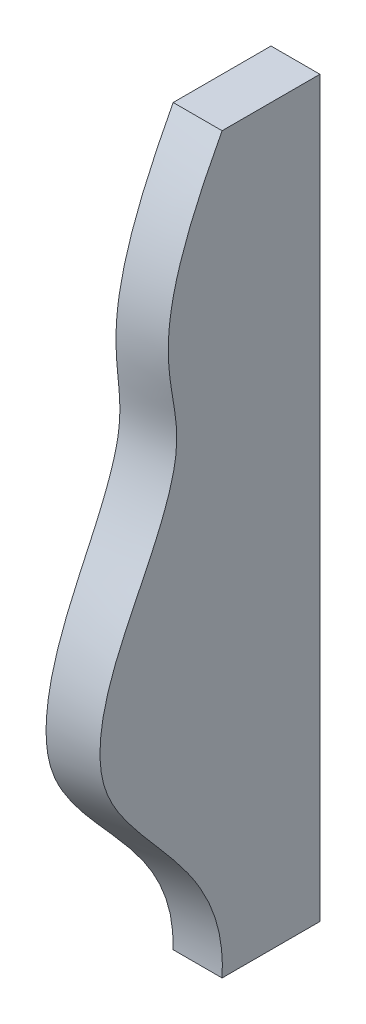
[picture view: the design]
ISO-10303-21;
HEADER;
FILE_DESCRIPTION(('STEP AP214'),'2;1');
FILE_NAME('part.step','',(''),(''),'','','');
FILE_SCHEMA(('AUTOMOTIVE_DESIGN { 1 0 10303 214 1 1 1 1 }'));
ENDSEC;
DATA;
#1=APPLICATION_CONTEXT('core data for automotive mechanical design processes');
#2=APPLICATION_PROTOCOL_DEFINITION('international standard','automotive_design',2000,#1);
#3=PRODUCT_CONTEXT('',#1,'mechanical');
#4=PRODUCT('Part','Part','',(#3));
#5=PRODUCT_RELATED_PRODUCT_CATEGORY('part','',(#4));
#6=PRODUCT_DEFINITION_FORMATION('','',#4);
#7=PRODUCT_DEFINITION_CONTEXT('part definition',#1,'design');
#8=PRODUCT_DEFINITION('design','',#6,#7);
#9=PRODUCT_DEFINITION_SHAPE('','',#8);
#10=(LENGTH_UNIT() NAMED_UNIT(*) SI_UNIT(.MILLI.,.METRE.));
#11=(NAMED_UNIT(*) PLANE_ANGLE_UNIT() SI_UNIT($,.RADIAN.));
#12=(NAMED_UNIT(*) SI_UNIT($,.STERADIAN.) SOLID_ANGLE_UNIT());
#13=UNCERTAINTY_MEASURE_WITH_UNIT(LENGTH_MEASURE(1.E-05),#10,'distance_accuracy_value','');
#14=(GEOMETRIC_REPRESENTATION_CONTEXT(3) GLOBAL_UNCERTAINTY_ASSIGNED_CONTEXT((#13)) GLOBAL_UNIT_ASSIGNED_CONTEXT((#10,
#11,#12)) REPRESENTATION_CONTEXT('',''));
#15=CARTESIAN_POINT('',(0.,0.,0.));
#16=DIRECTION('',(0.,0.,1.));
#17=DIRECTION('',(1.,0.,0.));
#18=AXIS2_PLACEMENT_3D('',#15,#16,#17);
#19=CARTESIAN_POINT('',(150.,375.,253.120113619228));
#20=DIRECTION('',(1.,0.,0.));
#21=DIRECTION('',(0.,0.,-1.));
#22=AXIS2_PLACEMENT_3D('',#19,#20,#21);
#23=PLANE('',#22);
#24=CARTESIAN_POINT('',(150.,375.,100.));
#25=CARTESIAN_POINT('',(150.,373.247296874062,100.949272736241));
#26=CARTESIAN_POINT('',(150.,371.49166332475,101.893144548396));
#27=CARTESIAN_POINT('',(150.,367.973911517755,103.76967532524));
#28=CARTESIAN_POINT('',(150.,366.211791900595,104.702331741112));
#29=CARTESIAN_POINT('',(150.,362.68094876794,106.555742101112));
#30=CARTESIAN_POINT('',(150.,360.912224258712,107.476494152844));
#31=CARTESIAN_POINT('',(150.,357.368027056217,109.305350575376));
#32=CARTESIAN_POINT('',(150.,355.592553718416,110.213453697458));
#33=CARTESIAN_POINT('',(150.,352.03469085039,112.016223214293));
#34=CARTESIAN_POINT('',(150.,350.252300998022,112.910888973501));
#35=CARTESIAN_POINT('',(150.,346.680410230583,114.685941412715));
#36=CARTESIAN_POINT('',(150.,344.89090927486,115.566328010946));
#37=CARTESIAN_POINT('',(150.,341.238005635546,117.344322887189));
#38=CARTESIAN_POINT('',(150.,339.374324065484,118.241358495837));
#39=CARTESIAN_POINT('',(150.,335.638765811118,120.018035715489));
#40=CARTESIAN_POINT('',(150.,333.766889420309,120.897677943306));
#41=CARTESIAN_POINT('',(150.,330.014609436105,122.638410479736));
#42=CARTESIAN_POINT('',(150.,328.134206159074,123.499501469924));
#43=CARTESIAN_POINT('',(150.,324.364498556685,125.20187965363));
#44=CARTESIAN_POINT('',(150.,322.475194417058,126.043167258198));
#45=CARTESIAN_POINT('',(150.,318.687262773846,127.704583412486));
#46=CARTESIAN_POINT('',(150.,316.788635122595,128.524711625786));
#47=CARTESIAN_POINT('',(150.,312.981585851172,130.142334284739));
#48=CARTESIAN_POINT('',(150.,311.073163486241,130.939826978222));
#49=CARTESIAN_POINT('',(150.,306.842771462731,132.67607155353));
#50=CARTESIAN_POINT('',(150.,304.518466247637,133.609144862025));
#51=CARTESIAN_POINT('',(150.,299.854413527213,135.436354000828));
#52=CARTESIAN_POINT('',(150.,297.51466504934,136.330487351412));
#53=CARTESIAN_POINT('',(150.,292.819220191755,138.076111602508));
#54=CARTESIAN_POINT('',(150.,290.463523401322,138.927601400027));
#55=CARTESIAN_POINT('',(150.,285.735557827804,140.583880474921));
#56=CARTESIAN_POINT('',(150.,283.363287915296,141.388666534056));
#57=CARTESIAN_POINT('',(150.,278.601413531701,142.947089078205));
#58=CARTESIAN_POINT('',(150.,276.211805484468,143.700714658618));
#59=CARTESIAN_POINT('',(150.,271.414338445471,145.151939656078));
#60=CARTESIAN_POINT('',(150.,269.006471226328,145.849511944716));
#61=CARTESIAN_POINT('',(150.,264.23211258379,147.166545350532));
#62=CARTESIAN_POINT('',(150.,261.866031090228,147.787488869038));
#63=CARTESIAN_POINT('',(150.,257.117326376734,148.964920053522));
#64=CARTESIAN_POINT('',(150.,254.73469992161,149.521394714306));
#65=CARTESIAN_POINT('',(150.,249.954521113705,150.563713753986));
#66=CARTESIAN_POINT('',(150.,247.556972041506,151.049573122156));
#67=CARTESIAN_POINT('',(150.,242.748569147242,151.944497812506));
#68=CARTESIAN_POINT('',(150.,240.337721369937,152.353595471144));
#69=CARTESIAN_POINT('',(150.,235.504389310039,153.089037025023));
#70=CARTESIAN_POINT('',(150.,233.081910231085,153.415414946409));
#71=CARTESIAN_POINT('',(150.,228.22708593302,153.979952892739));
#72=CARTESIAN_POINT('',(150.,225.794742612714,154.218129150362));
#73=CARTESIAN_POINT('',(150.,221.202606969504,154.57964961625));
#74=CARTESIAN_POINT('',(150.,219.043610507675,154.713043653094));
#75=CARTESIAN_POINT('',(150.,215.802375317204,154.857056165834));
#76=CARTESIAN_POINT('',(150.,214.721323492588,154.895715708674));
#77=CARTESIAN_POINT('',(150.,212.558715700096,154.954212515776));
#78=CARTESIAN_POINT('',(150.,211.477159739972,154.974050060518));
#79=CARTESIAN_POINT('',(150.,209.313700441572,154.994876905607));
#80=CARTESIAN_POINT('',(150.,208.231797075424,154.995863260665));
#81=CARTESIAN_POINT('',(150.,206.06815198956,154.979082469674));
#82=CARTESIAN_POINT('',(150.,204.986410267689,154.961315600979));
#83=CARTESIAN_POINT('',(150.,202.82338573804,154.907267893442));
#84=CARTESIAN_POINT('',(150.,201.742102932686,154.870986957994));
#85=CARTESIAN_POINT('',(150.,199.580299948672,154.780304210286));
#86=CARTESIAN_POINT('',(150.,198.499779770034,154.725902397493));
#87=CARTESIAN_POINT('',(150.,196.340060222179,154.599554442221));
#88=CARTESIAN_POINT('',(150.,195.26086057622,154.52761301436));
#89=CARTESIAN_POINT('',(150.,193.103718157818,154.366915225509));
#90=CARTESIAN_POINT('',(150.,192.025775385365,154.278158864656));
#91=CARTESIAN_POINT('',(150.,189.872196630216,154.08483354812));
#92=CARTESIAN_POINT('',(150.,188.796559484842,153.980277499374));
#93=CARTESIAN_POINT('',(150.,186.646826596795,153.756414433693));
#94=CARTESIAN_POINT('',(150.,185.572730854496,153.637107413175));
#95=CARTESIAN_POINT('',(150.,183.411630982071,153.383350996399));
#96=CARTESIAN_POINT('',(150.,182.324648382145,153.248718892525));
#97=CARTESIAN_POINT('',(150.,180.152274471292,152.967218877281));
#98=CARTESIAN_POINT('',(150.,179.066883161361,152.820350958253));
#99=CARTESIAN_POINT('',(150.,176.897957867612,152.51620875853));
#100=CARTESIAN_POINT('',(150.,175.814423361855,152.358938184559));
#101=CARTESIAN_POINT('',(150.,173.648624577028,152.03591591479));
#102=CARTESIAN_POINT('',(150.,172.566360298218,151.870164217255));
#103=CARTESIAN_POINT('',(150.,170.402658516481,151.532314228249));
#104=CARTESIAN_POINT('',(150.,169.321221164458,151.360214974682));
#105=CARTESIAN_POINT('',(150.,167.158990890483,151.012030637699));
#106=CARTESIAN_POINT('',(150.,166.078197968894,150.835945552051));
#107=CARTESIAN_POINT('',(150.,163.916447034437,150.482217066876));
#108=CARTESIAN_POINT('',(150.,162.835489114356,150.304573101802));
#109=CARTESIAN_POINT('',(150.,160.673385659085,149.950433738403));
#110=CARTESIAN_POINT('',(150.,159.592240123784,149.77393834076));
#111=CARTESIAN_POINT('',(150.,156.346709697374,149.250094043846));
#112=CARTESIAN_POINT('',(150.,154.181366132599,148.908578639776));
#113=CARTESIAN_POINT('',(150.,149.842848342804,148.263753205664));
#114=CARTESIAN_POINT('',(150.,147.669668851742,147.960477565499));
#115=CARTESIAN_POINT('',(150.,143.945168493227,147.494438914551));
#116=CARTESIAN_POINT('',(150.,142.395781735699,147.316405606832));
#117=CARTESIAN_POINT('',(150.,139.292748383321,146.999390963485));
#118=CARTESIAN_POINT('',(150.,137.739101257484,146.860414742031));
#119=CARTESIAN_POINT('',(150.,134.629263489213,146.628850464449));
#120=CARTESIAN_POINT('',(150.,133.073075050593,146.536233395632));
#121=CARTESIAN_POINT('',(150.,129.959950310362,146.40352294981));
#122=CARTESIAN_POINT('',(150.,128.403016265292,146.36337778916));
#123=CARTESIAN_POINT('',(150.,125.290187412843,146.340373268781));
#124=CARTESIAN_POINT('',(150.,123.734293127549,146.357456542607));
#125=CARTESIAN_POINT('',(150.,121.402495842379,146.428465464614));
#126=CARTESIAN_POINT('',(150.,120.625848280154,146.459679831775));
#127=CARTESIAN_POINT('',(150.,119.073310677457,146.537483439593));
#128=CARTESIAN_POINT('',(150.,118.297420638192,146.584072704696));
#129=CARTESIAN_POINT('',(150.,116.754063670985,146.692307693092));
#130=CARTESIAN_POINT('',(150.,115.986586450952,146.753806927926));
#131=CARTESIAN_POINT('',(150.,114.453020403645,146.892166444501));
#132=CARTESIAN_POINT('',(150.,113.686931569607,146.969026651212));
#133=CARTESIAN_POINT('',(150.,112.155915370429,147.138207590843));
#134=CARTESIAN_POINT('',(150.,111.390989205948,147.23053919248));
#135=CARTESIAN_POINT('',(150.,109.863132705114,147.430438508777));
#136=CARTESIAN_POINT('',(150.,109.100202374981,147.538006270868));
#137=CARTESIAN_POINT('',(150.,107.575692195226,147.76738947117));
#138=CARTESIAN_POINT('',(150.,106.814114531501,147.889219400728));
#139=CARTESIAN_POINT('',(150.,105.293205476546,148.146122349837));
#140=CARTESIAN_POINT('',(150.,104.53387408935,148.281195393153));
#141=CARTESIAN_POINT('',(150.,102.257812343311,148.705255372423));
#142=CARTESIAN_POINT('',(150.,100.744522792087,149.012852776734));
#143=CARTESIAN_POINT('',(150.,97.7266105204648,149.671799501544));
#144=CARTESIAN_POINT('',(150.,96.2219937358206,150.023175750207));
#145=CARTESIAN_POINT('',(150.,93.2224352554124,150.764478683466));
#146=CARTESIAN_POINT('',(150.,91.7274928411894,151.15440246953));
#147=CARTESIAN_POINT('',(150.,88.8734457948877,151.934017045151));
#148=CARTESIAN_POINT('',(150.,87.5135768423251,152.320921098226));
#149=CARTESIAN_POINT('',(150.,84.8014690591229,153.120657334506));
#150=CARTESIAN_POINT('',(150.,83.4492304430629,153.533490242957));
#151=CARTESIAN_POINT('',(150.,79.4057115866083,154.80651312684));
#152=CARTESIAN_POINT('',(150.,76.7254442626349,155.701832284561));
#153=CARTESIAN_POINT('',(150.,71.3931373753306,157.572090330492));
#154=CARTESIAN_POINT('',(150.,68.7410970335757,158.547027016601));
#155=CARTESIAN_POINT('',(150.,63.4621878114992,160.564404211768));
#156=CARTESIAN_POINT('',(150.,60.8353249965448,161.606860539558));
#157=CARTESIAN_POINT('',(150.,55.6042279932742,163.748143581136));
#158=CARTESIAN_POINT('',(150.,52.9999978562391,164.846980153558));
#159=CARTESIAN_POINT('',(150.,47.8118804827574,167.090640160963));
#160=CARTESIAN_POINT('',(150.,45.2279907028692,168.235457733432));
#161=CARTESIAN_POINT('',(150.,40.026064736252,170.584884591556));
#162=CARTESIAN_POINT('',(150.,37.4083611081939,171.790228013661));
#163=CARTESIAN_POINT('',(150.,32.1876338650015,174.229472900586));
#164=CARTESIAN_POINT('',(150.,29.5846047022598,175.463362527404));
#165=CARTESIAN_POINT('',(150.,24.3888098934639,177.951046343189));
#166=CARTESIAN_POINT('',(150.,21.796042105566,179.20483607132));
#167=CARTESIAN_POINT('',(150.,16.6164102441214,181.723778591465));
#168=CARTESIAN_POINT('',(150.,14.0295455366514,182.988930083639));
#169=CARTESIAN_POINT('',(150.,8.85734206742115,185.522017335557));
#170=CARTESIAN_POINT('',(150.,6.27200323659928,186.789952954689));
#171=CARTESIAN_POINT('',(150.,1.09839768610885,189.319873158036));
#172=CARTESIAN_POINT('',(150.,-1.48986904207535,190.581857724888));
#173=CARTESIAN_POINT('',(150.,-6.67249249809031,193.090210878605));
#174=CARTESIAN_POINT('',(150.,-9.26684582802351,194.336586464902));
#175=CARTESIAN_POINT('',(150.,-14.4672144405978,196.804881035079));
#176=CARTESIAN_POINT('',(150.,-17.0732297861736,198.026799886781));
#177=CARTESIAN_POINT('',(150.,-22.3012873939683,200.436339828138));
#178=CARTESIAN_POINT('',(150.,-24.9233304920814,201.623959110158));
#179=CARTESIAN_POINT('',(150.,-30.1879778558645,203.95467835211));
#180=CARTESIAN_POINT('',(150.,-32.8305870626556,205.097767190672));
#181=CARTESIAN_POINT('',(150.,-38.141081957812,207.32879450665));
#182=CARTESIAN_POINT('',(150.,-40.8089828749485,208.416696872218));
#183=CARTESIAN_POINT('',(150.,-46.1749850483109,210.52626355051));
#184=CARTESIAN_POINT('',(150.,-48.8731212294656,211.547839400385));
#185=CARTESIAN_POINT('',(150.,-54.2622198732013,213.497694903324));
#186=CARTESIAN_POINT('',(150.,-56.9527951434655,214.427040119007));
#187=CARTESIAN_POINT('',(150.,-62.3651819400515,216.195670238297));
#188=CARTESIAN_POINT('',(150.,-65.0870099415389,217.034904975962));
#189=CARTESIAN_POINT('',(150.,-70.558973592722,218.60899420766));
#190=CARTESIAN_POINT('',(150.,-73.3090901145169,219.343914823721));
#191=CARTESIAN_POINT('',(150.,-78.8346826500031,220.695173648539));
#192=CARTESIAN_POINT('',(150.,-81.6101206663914,221.31166614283));
#193=CARTESIAN_POINT('',(150.,-87.1833836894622,222.411785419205));
#194=CARTESIAN_POINT('',(150.,-89.981172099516,222.895596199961));
#195=CARTESIAN_POINT('',(150.,-95.5964427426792,223.715672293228));
#196=CARTESIAN_POINT('',(150.,-98.4139080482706,224.052051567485));
#197=CARTESIAN_POINT('',(150.,-103.392704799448,224.500985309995));
#198=CARTESIAN_POINT('',(150.,-105.55097045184,224.647721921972));
#199=CARTESIAN_POINT('',(150.,-109.872459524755,224.8387691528));
#200=CARTESIAN_POINT('',(150.,-112.035683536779,224.883066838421));
#201=CARTESIAN_POINT('',(150.,-116.362228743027,224.861610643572));
#202=CARTESIAN_POINT('',(150.,-118.525549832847,224.795829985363));
#203=CARTESIAN_POINT('',(150.,-122.836806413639,224.54717432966));
#204=CARTESIAN_POINT('',(150.,-124.984768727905,224.364774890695));
#205=CARTESIAN_POINT('',(150.,-129.266440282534,223.876347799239));
#206=CARTESIAN_POINT('',(150.,-131.400151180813,223.570334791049));
#207=CARTESIAN_POINT('',(150.,-135.644256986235,222.828518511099));
#208=CARTESIAN_POINT('',(150.,-137.754661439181,222.392770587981));
#209=CARTESIAN_POINT('',(150.,-141.112337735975,221.586138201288));
#210=CARTESIAN_POINT('',(150.,-142.370030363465,221.258050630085));
#211=CARTESIAN_POINT('',(150.,-144.871608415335,220.551969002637));
#212=CARTESIAN_POINT('',(150.,-146.115492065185,220.173968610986));
#213=CARTESIAN_POINT('',(150.,-147.968971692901,219.56920991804));
#214=CARTESIAN_POINT('',(150.,-148.584785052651,219.361314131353));
#215=CARTESIAN_POINT('',(150.,-149.812005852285,218.932879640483));
#216=CARTESIAN_POINT('',(150.,-150.423413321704,218.712341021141));
#217=CARTESIAN_POINT('',(150.,-151.641610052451,218.258652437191));
#218=CARTESIAN_POINT('',(150.,-152.24839875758,218.0255009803));
#219=CARTESIAN_POINT('',(150.,-153.457265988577,217.547307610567));
#220=CARTESIAN_POINT('',(150.,-154.05934448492,217.302265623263));
#221=CARTESIAN_POINT('',(150.,-155.858371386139,216.550323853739));
#222=CARTESIAN_POINT('',(150.,-157.048295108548,216.026539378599));
#223=CARTESIAN_POINT('',(150.,-159.414521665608,214.936937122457));
#224=CARTESIAN_POINT('',(150.,-160.590749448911,214.37095709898));
#225=CARTESIAN_POINT('',(150.,-162.341871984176,213.49570562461));
#226=CARTESIAN_POINT('',(150.,-162.923378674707,213.19957361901));
#227=CARTESIAN_POINT('',(150.,-164.082107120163,212.599041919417));
#228=CARTESIAN_POINT('',(150.,-164.659328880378,212.294642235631));
#229=CARTESIAN_POINT('',(150.,-166.384790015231,211.369514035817));
#230=CARTESIAN_POINT('',(150.,-167.52668940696,210.736924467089));
#231=CARTESIAN_POINT('',(150.,-169.794216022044,209.44307125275));
#232=CARTESIAN_POINT('',(150.,-170.919841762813,208.781805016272));
#233=CARTESIAN_POINT('',(150.,-173.155316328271,207.43347391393));
#234=CARTESIAN_POINT('',(150.,-174.26516706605,206.746412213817));
#235=CARTESIAN_POINT('',(150.,-177.21351393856,204.877796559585));
#236=CARTESIAN_POINT('',(150.,-179.038697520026,203.675206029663));
#237=CARTESIAN_POINT('',(150.,-182.651542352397,201.21576837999));
#238=CARTESIAN_POINT('',(150.,-184.439209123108,199.958929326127));
#239=CARTESIAN_POINT('',(150.,-187.982530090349,197.399882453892));
#240=CARTESIAN_POINT('',(150.,-189.738174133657,196.097660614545));
#241=CARTESIAN_POINT('',(150.,-193.222330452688,193.45604874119));
#242=CARTESIAN_POINT('',(150.,-194.950831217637,192.116643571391));
#243=CARTESIAN_POINT('',(150.,-198.385146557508,189.408259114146));
#244=CARTESIAN_POINT('',(150.,-200.090955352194,188.039272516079));
#245=CARTESIAN_POINT('',(150.,-203.483955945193,185.278836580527));
#246=CARTESIAN_POINT('',(150.,-205.17114968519,183.887389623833));
#247=CARTESIAN_POINT('',(150.,-208.538611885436,181.082129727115));
#248=CARTESIAN_POINT('',(150.,-210.218823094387,179.668248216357));
#249=CARTESIAN_POINT('',(150.,-213.569092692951,176.829923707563));
#250=CARTESIAN_POINT('',(150.,-215.239154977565,175.405485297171));
#251=CARTESIAN_POINT('',(150.,-218.573761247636,172.551034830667));
#252=CARTESIAN_POINT('',(150.,-220.238306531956,171.121024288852));
#253=CARTESIAN_POINT('',(150.,-223.566307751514,168.260179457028));
#254=CARTESIAN_POINT('',(150.,-225.229763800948,166.829345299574));
#255=CARTESIAN_POINT('',(150.,-228.559864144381,163.971425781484));
#256=CARTESIAN_POINT('',(150.,-230.22650839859,162.544340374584));
#257=CARTESIAN_POINT('',(150.,-233.567153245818,159.69836874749));
#258=CARTESIAN_POINT('',(150.,-235.241154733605,158.279483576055));
#259=CARTESIAN_POINT('',(150.,-238.943589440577,155.165857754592));
#260=CARTESIAN_POINT('',(150.,-240.974492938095,153.474046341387));
#261=CARTESIAN_POINT('',(150.,-245.058792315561,150.117229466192));
#262=CARTESIAN_POINT('',(150.,-247.112190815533,148.452227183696));
#263=CARTESIAN_POINT('',(150.,-251.247283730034,145.157557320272));
#264=CARTESIAN_POINT('',(150.,-253.328978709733,143.527890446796));
#265=CARTESIAN_POINT('',(150.,-257.52645198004,140.312400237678));
#266=CARTESIAN_POINT('',(150.,-259.642234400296,138.726582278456));
#267=CARTESIAN_POINT('',(150.,-263.913685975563,135.607315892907));
#268=CARTESIAN_POINT('',(150.,-266.069373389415,134.073892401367));
#269=CARTESIAN_POINT('',(150.,-270.410235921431,131.07920294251));
#270=CARTESIAN_POINT('',(150.,-272.595136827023,129.6175405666));
#271=CARTESIAN_POINT('',(150.,-277.011675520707,126.765387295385));
#272=CARTESIAN_POINT('',(150.,-279.243322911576,125.374911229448));
#273=CARTESIAN_POINT('',(150.,-283.754686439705,122.675818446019));
#274=CARTESIAN_POINT('',(150.,-286.034385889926,121.36717391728));
#275=CARTESIAN_POINT('',(150.,-290.642791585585,118.841828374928));
#276=CARTESIAN_POINT('',(150.,-292.971472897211,117.625081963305));
#277=CARTESIAN_POINT('',(150.,-297.678466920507,115.292847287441));
#278=CARTESIAN_POINT('',(150.,-300.056766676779,114.177332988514));
#279=CARTESIAN_POINT('',(150.,-304.079067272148,112.402026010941));
#280=CARTESIAN_POINT('',(150.,-305.709849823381,111.712168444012));
#281=CARTESIAN_POINT('',(150.,-308.992918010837,110.38501026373));
#282=CARTESIAN_POINT('',(150.,-310.645205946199,109.747715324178));
#283=CARTESIAN_POINT('',(150.,-313.969977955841,108.528134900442));
#284=CARTESIAN_POINT('',(150.,-315.642462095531,107.945849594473));
#285=CARTESIAN_POINT('',(150.,-319.006224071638,106.838340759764));
#286=CARTESIAN_POINT('',(150.,-320.697501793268,106.313116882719));
#287=CARTESIAN_POINT('',(150.,-324.097303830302,105.321404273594));
#288=CARTESIAN_POINT('',(150.,-325.805829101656,104.854918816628));
#289=CARTESIAN_POINT('',(150.,-329.239156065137,103.981781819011));
#290=CARTESIAN_POINT('',(150.,-330.963966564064,103.575164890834));
#291=CARTESIAN_POINT('',(150.,-334.426998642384,102.822956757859));
#292=CARTESIAN_POINT('',(150.,-336.165221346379,102.477370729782));
#293=CARTESIAN_POINT('',(150.,-339.652675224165,101.847759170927));
#294=CARTESIAN_POINT('',(150.,-341.401905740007,101.563729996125));
#295=CARTESIAN_POINT('',(150.,-344.908880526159,101.05730537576));
#296=CARTESIAN_POINT('',(150.,-346.666622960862,100.834897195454));
#297=CARTESIAN_POINT('',(150.,-350.188118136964,100.45134575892));
#298=CARTESIAN_POINT('',(150.,-351.951868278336,100.290178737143));
#299=CARTESIAN_POINT('',(150.,-354.603881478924,100.093495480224));
#300=CARTESIAN_POINT('',(150.,-355.490527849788,100.035382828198));
#301=CARTESIAN_POINT('',(150.,-357.264510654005,99.9342395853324));
#302=CARTESIAN_POINT('',(150.,-358.151846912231,99.8912059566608));
#303=CARTESIAN_POINT('',(150.,-359.927005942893,99.8200640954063));
#304=CARTESIAN_POINT('',(150.,-360.814828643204,99.7919540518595));
#305=CARTESIAN_POINT('',(150.,-362.590773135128,99.7504859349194));
#306=CARTESIAN_POINT('',(150.,-363.478894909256,99.7371271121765));
#307=CARTESIAN_POINT('',(150.,-365.253451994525,99.7249882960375));
#308=CARTESIAN_POINT('',(150.,-366.139887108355,99.7261790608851));
#309=CARTESIAN_POINT('',(150.,-367.912671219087,99.7428716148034));
#310=CARTESIAN_POINT('',(150.,-368.79902020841,99.7583742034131));
#311=CARTESIAN_POINT('',(150.,-370.57143991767,99.8034830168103));
#312=CARTESIAN_POINT('',(150.,-371.457510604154,99.8330905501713));
#313=CARTESIAN_POINT('',(150.,-373.229184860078,99.9061883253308));
#314=CARTESIAN_POINT('',(150.,-374.114788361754,99.9496802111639));
#315=CARTESIAN_POINT('',(150.,-375.,100.));
#316=B_SPLINE_CURVE_WITH_KNOTS('',3,(#24,#25,#26,#27,#28,#29,#30,#31,#32,#33,#34,#35,#36,#37,
#38,#39,#40,#41,#42,#43,#44,#45,#46,#47,#48,#49,#50,#51,#52,#53,#54,#55,#56,#57,#58,#59,#60,#61,
#62,#63,#64,#65,#66,#67,#68,#69,#70,#71,#72,#73,#74,#75,#76,#77,#78,#79,#80,#81,#82,#83,#84,#85,
#86,#87,#88,#89,#90,#91,#92,#93,#94,#95,#96,#97,#98,#99,#100,#101,#102,#103,#104,#105,#106,#107,
#108,#109,#110,#111,#112,#113,#114,#115,#116,#117,#118,#119,#120,#121,#122,#123,#124,#125,#126,
#127,#128,#129,#130,#131,#132,#133,#134,#135,#136,#137,#138,#139,#140,#141,#142,#143,#144,#145,
#146,#147,#148,#149,#150,#151,#152,#153,#154,#155,#156,#157,#158,#159,#160,#161,#162,#163,#164,
#165,#166,#167,#168,#169,#170,#171,#172,#173,#174,#175,#176,#177,#178,#179,#180,#181,#182,#183,
#184,#185,#186,#187,#188,#189,#190,#191,#192,#193,#194,#195,#196,#197,#198,#199,#200,#201,#202,
#203,#204,#205,#206,#207,#208,#209,#210,#211,#212,#213,#214,#215,#216,#217,#218,#219,#220,#221,
#222,#223,#224,#225,#226,#227,#228,#229,#230,#231,#232,#233,#234,#235,#236,#237,#238,#239,#240,
#241,#242,#243,#244,#245,#246,#247,#248,#249,#250,#251,#252,#253,#254,#255,#256,#257,#258,#259,
#260,#261,#262,#263,#264,#265,#266,#267,#268,#269,#270,#271,#272,#273,#274,#275,#276,#277,#278,
#279,#280,#281,#282,#283,#284,#285,#286,#287,#288,#289,#290,#291,#292,#293,#294,#295,#296,#297,
#298,#299,#300,#301,#302,#303,#304,#305,#306,#307,#308,#309,#310,#311,#312,#313,#314,#315),
.UNSPECIFIED.,.F.,.F.,(4,2,2,2,2,2,2,2,2,2,2,2,2,2,2,2,2,2,2,2,2,2,2,2,2,2,2,2,2,2,2,2,2,2,2,2,
2,2,2,2,2,2,2,2,2,2,2,2,2,2,2,2,2,2,2,2,2,2,2,2,2,2,2,2,2,2,2,2,2,2,2,2,2,2,2,2,2,2,2,2,2,2,2,2,
2,2,2,2,2,2,2,2,2,2,2,2,2,2,2,2,2,2,2,2,2,2,2,2,2,2,2,2,2,2,2,2,2,2,2,2,2,2,2,2,2,2,2,2,2,2,2,2,
2,2,2,2,2,2,2,2,2,2,2,2,2,4),(0.,5.97977851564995,11.9608912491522,17.9429433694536,
23.9255819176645,29.9085025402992,35.8914574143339,42.096357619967,48.3010373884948,
54.5054888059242,60.7098113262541,66.9142324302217,73.1191325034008,80.6326018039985,
88.146548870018,95.6606901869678,103.175348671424,110.691603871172,118.211475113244,
125.549257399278,132.888517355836,140.226217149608,147.560818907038,154.89239871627,
162.222628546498,168.710611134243,171.955701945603,175.200744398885,178.446293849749,
181.6917953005,184.937313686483,188.182832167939,191.427479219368,194.672126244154,
197.914136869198,201.15614828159,204.441934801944,207.727723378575,211.01234738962,
214.296972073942,217.58209667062,220.867223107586,224.153595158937,227.439969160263,
234.016170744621,240.598244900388,245.276594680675,249.955556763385,254.631586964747,
259.302998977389,263.969729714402,266.301427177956,268.633128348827,270.942788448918,
273.252437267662,275.563715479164,277.875000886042,280.188655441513,282.502314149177,
287.134206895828,291.768962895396,296.403370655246,300.64460225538,304.885952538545,
313.361858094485,321.837529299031,330.31519344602,338.794345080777,347.272419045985,
355.917819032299,364.559695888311,373.199662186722,381.838652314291,390.477215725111,
399.115804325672,407.750369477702,416.384981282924,425.020047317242,433.657256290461,
442.300046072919,450.954135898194,459.492414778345,468.035422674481,476.572990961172,
485.099360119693,493.613844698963,502.121736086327,508.609315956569,515.097714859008,
521.587692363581,528.051371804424,534.514285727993,540.974446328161,544.872915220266,
548.771879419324,550.721645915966,552.67139933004,554.621383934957,556.571380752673,
560.470785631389,564.386044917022,566.343690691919,568.301334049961,572.217076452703,
576.133173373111,580.048791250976,586.604764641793,593.159766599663,599.716811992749,
606.276566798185,612.837961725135,619.398665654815,625.986424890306,632.571472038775,
639.154839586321,645.737344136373,652.319767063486,658.903013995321,666.832611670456,
674.763142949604,682.693832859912,690.625490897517,698.560872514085,706.445858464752,
714.332480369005,722.216407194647,730.096413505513,737.97438747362,743.285652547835,
748.597490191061,753.909345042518,759.221167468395,764.53328593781,769.848463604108,
775.16409189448,780.479405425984,785.793619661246,791.105769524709,793.771310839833,
796.436314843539,799.100995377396,801.765540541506,804.424731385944,807.084070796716,
809.743656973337,812.403558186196),.UNSPECIFIED.);
#317=CARTESIAN_POINT('',(150.,375.,100.));
#318=VERTEX_POINT('',#317);
#319=CARTESIAN_POINT('',(150.,-375.,100.));
#320=VERTEX_POINT('',#319);
#321=EDGE_CURVE('E88',#318,#320,#316,.T.);
#322=ORIENTED_EDGE('',*,*,#321,.T.);
#323=DIRECTION('',(0.,0.,-1.));
#324=VECTOR('',#323,1.);
#325=CARTESIAN_POINT('',(150.,-375.,253.120113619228));
#326=LINE('',#325,#324);
#327=CARTESIAN_POINT('',(150.,-375.,0.));
#328=VERTEX_POINT('',#327);
#329=EDGE_CURVE('E50',#320,#328,#326,.T.);
#330=ORIENTED_EDGE('',*,*,#329,.T.);
#331=DIRECTION('',(0.,-1.,0.));
#332=VECTOR('',#331,1.);
#333=CARTESIAN_POINT('',(150.,375.,0.));
#334=LINE('',#333,#332);
#335=CARTESIAN_POINT('',(150.,375.,0.));
#336=VERTEX_POINT('',#335);
#337=EDGE_CURVE('E87',#336,#328,#334,.T.);
#338=ORIENTED_EDGE('',*,*,#337,.F.);
#339=DIRECTION('',(0.,0.,-1.));
#340=VECTOR('',#339,1.);
#341=CARTESIAN_POINT('',(150.,375.,253.120113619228));
#342=LINE('',#341,#340);
#343=EDGE_CURVE('E65',#318,#336,#342,.T.);
#344=ORIENTED_EDGE('',*,*,#343,.F.);
#345=EDGE_LOOP('',(#322,#330,#338,#344));
#346=FACE_BOUND('',#345,.T.);
#347=ADVANCED_FACE('F35',(#346),#23,.T.);
#348=CARTESIAN_POINT('',(0.,0.,0.));
#349=DIRECTION('',(0.,0.,-1.));
#350=DIRECTION('',(-1.,0.,0.));
#351=AXIS2_PLACEMENT_3D('',#348,#349,#350);
#352=PLANE('',#351);
#353=DIRECTION('',(1.,0.,0.));
#354=VECTOR('',#353,1.);
#355=CARTESIAN_POINT('',(-750.,-375.,0.));
#356=LINE('',#355,#354);
#357=CARTESIAN_POINT('',(100.,-375.,0.));
#358=VERTEX_POINT('',#357);
#359=EDGE_CURVE('E79',#358,#328,#356,.T.);
#360=ORIENTED_EDGE('',*,*,#359,.F.);
#361=DIRECTION('',(0.,1.,0.));
#362=VECTOR('',#361,1.);
#363=CARTESIAN_POINT('',(99.9999999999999,375.,0.));
#364=LINE('',#363,#362);
#365=CARTESIAN_POINT('',(99.9999999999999,375.,0.));
#366=VERTEX_POINT('',#365);
#367=EDGE_CURVE('E157',#358,#366,#364,.T.);
#368=ORIENTED_EDGE('',*,*,#367,.T.);
#369=DIRECTION('',(-1.,0.,0.));
#370=VECTOR('',#369,1.);
#371=CARTESIAN_POINT('',(-750.,375.,0.));
#372=LINE('',#371,#370);
#373=EDGE_CURVE('E93',#336,#366,#372,.T.);
#374=ORIENTED_EDGE('',*,*,#373,.F.);
#375=ORIENTED_EDGE('',*,*,#337,.T.);
#376=EDGE_LOOP('',(#360,#368,#374,#375));
#377=FACE_BOUND('',#376,.T.);
#378=ADVANCED_FACE('F91',(#377),#352,.T.);
#379=CARTESIAN_POINT('',(750.,-375.,100.));
#380=CARTESIAN_POINT('',(750.,-302.078506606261,100.));
#381=CARTESIAN_POINT('',(750.,-224.483786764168,100.));
#382=CARTESIAN_POINT('',(750.,-61.5160152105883,100.));
#383=CARTESIAN_POINT('',(750.,39.4445673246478,100.));
#384=CARTESIAN_POINT('',(750.,211.849847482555,100.));
#385=CARTESIAN_POINT('',(750.,298.882075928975,100.));
#386=CARTESIAN_POINT('',(750.,375.,100.));
#387=CARTESIAN_POINT('',(669.085175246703,-375.,100.));
#388=CARTESIAN_POINT('',(669.085175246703,-302.078506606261,100.));
#389=CARTESIAN_POINT('',(669.085175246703,-234.282472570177,121.198481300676));
#390=CARTESIAN_POINT('',(669.085175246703,-62.2283080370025,120.288550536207));
#391=CARTESIAN_POINT('',(669.085175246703,68.0647781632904,82.7868169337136));
#392=CARTESIAN_POINT('',(669.085175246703,240.312514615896,73.0426687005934));
#393=CARTESIAN_POINT('',(669.085175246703,298.882075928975,100.));
#394=CARTESIAN_POINT('',(669.085175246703,375.,100.));
#395=CARTESIAN_POINT('',(500.445116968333,-375.,100.));
#396=CARTESIAN_POINT('',(517.991528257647,-284.627602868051,95.5040591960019));
#397=CARTESIAN_POINT('',(530.038001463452,-221.673003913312,150.719602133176));
#398=CARTESIAN_POINT('',(473.74510655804,-71.7416270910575,167.060530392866));
#399=CARTESIAN_POINT('',(387.213321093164,45.6135081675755,91.591323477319));
#400=CARTESIAN_POINT('',(378.694107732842,207.638743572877,66.6461848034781));
#401=CARTESIAN_POINT('',(433.17831170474,253.396603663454,122.492891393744));
#402=CARTESIAN_POINT('',(500.445116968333,375.,100.));
#403=CARTESIAN_POINT('',(285.091607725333,-375.,100.));
#404=CARTESIAN_POINT('',(309.270321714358,-264.297524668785,86.4064578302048));
#405=CARTESIAN_POINT('',(325.856840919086,-200.08226970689,164.07204721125));
#406=CARTESIAN_POINT('',(247.47112957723,-80.9425320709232,234.992870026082));
#407=CARTESIAN_POINT('',(127.240382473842,2.40271344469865,186.756001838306));
#408=CARTESIAN_POINT('',(115.567806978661,152.518027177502,151.057444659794));
#409=CARTESIAN_POINT('',(191.428893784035,202.025100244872,189.039851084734));
#410=CARTESIAN_POINT('',(285.091607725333,375.,100.));
#411=CARTESIAN_POINT('',(47.4554331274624,-375.,100.));
#412=CARTESIAN_POINT('',(51.0669239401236,-278.639867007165,99.5141662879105));
#413=CARTESIAN_POINT('',(52.9210710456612,-231.452124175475,201.325948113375));
#414=CARTESIAN_POINT('',(3.18149891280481,-90.8615864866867,272.445475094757));
#415=CARTESIAN_POINT('',(-61.0346058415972,45.7948958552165,186.157760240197));
#416=CARTESIAN_POINT('',(-59.6612105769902,205.286893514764,133.941969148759));
#417=CARTESIAN_POINT('',(-11.8049718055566,220.40073671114,189.8209162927));
#418=CARTESIAN_POINT('',(47.4554331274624,375.,100.));
#419=CARTESIAN_POINT('',(-175.903454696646,-375.,100.));
#420=CARTESIAN_POINT('',(-199.823715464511,-320.588060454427,126.731848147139));
#421=CARTESIAN_POINT('',(-216.967937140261,-300.821135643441,242.921959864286));
#422=CARTESIAN_POINT('',(-184.265304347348,-55.1410097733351,206.147478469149));
#423=CARTESIAN_POINT('',(-119.865061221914,249.096629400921,-32.5779079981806));
#424=CARTESIAN_POINT('',(-104.641938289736,431.262460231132,-94.4845569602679));
#425=CARTESIAN_POINT('',(-136.623034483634,348.137040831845,60.785640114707));
#426=CARTESIAN_POINT('',(-175.903454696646,375.,100.));
#427=CARTESIAN_POINT('',(-355.235514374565,-375.,100.));
#428=CARTESIAN_POINT('',(-319.200833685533,-282.590755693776,58.2859511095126));
#429=CARTESIAN_POINT('',(-293.075279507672,-226.888141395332,104.97090627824));
#430=CARTESIAN_POINT('',(-324.119079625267,-68.6572837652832,122.102733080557));
#431=CARTESIAN_POINT('',(-398.972481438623,73.039345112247,53.3701087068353));
#432=CARTESIAN_POINT('',(-423.398679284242,233.384819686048,47.4380317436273));
#433=CARTESIAN_POINT('',(-392.720188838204,253.575952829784,124.952096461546));
#434=CARTESIAN_POINT('',(-355.235514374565,375.,100.));
#435=CARTESIAN_POINT('',(-536.684515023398,-375.,100.));
#436=CARTESIAN_POINT('',(-494.827225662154,-277.129657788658,52.0422385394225));
#437=CARTESIAN_POINT('',(-464.573647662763,-205.017596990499,67.039018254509));
#438=CARTESIAN_POINT('',(-506.334367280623,-72.2467511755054,96.5036749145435));
#439=CARTESIAN_POINT('',(-600.216684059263,9.35641022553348,95.9941925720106));
#440=CARTESIAN_POINT('',(-628.122542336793,166.946160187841,106.349064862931));
#441=CARTESIAN_POINT('',(-587.011939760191,237.095914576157,138.331902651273));
#442=CARTESIAN_POINT('',(-536.684515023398,375.,100.));
#443=CARTESIAN_POINT('',(-644.685568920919,-375.,100.));
#444=CARTESIAN_POINT('',(-644.685568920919,-302.078506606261,100.));
#445=CARTESIAN_POINT('',(-644.685568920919,-237.237234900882,127.59081546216));
#446=CARTESIAN_POINT('',(-644.685568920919,-62.4430976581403,126.406497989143));
#447=CARTESIAN_POINT('',(-644.685568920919,76.6951111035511,77.5962366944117));
#448=CARTESIAN_POINT('',(-644.685568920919,248.895340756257,64.9137717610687));
#449=CARTESIAN_POINT('',(-644.685568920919,298.882075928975,100.));
#450=CARTESIAN_POINT('',(-644.685568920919,375.,100.));
#451=CARTESIAN_POINT('',(-750.,-375.,100.));
#452=CARTESIAN_POINT('',(-750.,-302.078506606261,100.));
#453=CARTESIAN_POINT('',(-750.,-224.483786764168,100.));
#454=CARTESIAN_POINT('',(-750.,-61.5160152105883,100.));
#455=CARTESIAN_POINT('',(-750.,39.4445673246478,100.));
#456=CARTESIAN_POINT('',(-750.,211.849847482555,100.));
#457=CARTESIAN_POINT('',(-750.,298.882075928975,100.));
#458=CARTESIAN_POINT('',(-750.,375.,100.));
#459=B_SPLINE_SURFACE_WITH_KNOTS('',3,3,((#379,#380,#381,#382,#383,#384,#385,#386),(#387,#388,
#389,#390,#391,#392,#393,#394),(#395,#396,#397,#398,#399,#400,#401,#402),(#403,#404,#405,#406,
#407,#408,#409,#410),(#411,#412,#413,#414,#415,#416,#417,#418),(#419,#420,#421,#422,#423,#424,
#425,#426),(#427,#428,#429,#430,#431,#432,#433,#434),(#435,#436,#437,#438,#439,#440,#441,#442),
(#443,#444,#445,#446,#447,#448,#449,#450),(#451,#452,#453,#454,#455,#456,#457,#458)),
.UNSPECIFIED.,.F.,.F.,.F.,(4,1,1,1,1,1,1,4),(4,1,1,1,1,4),(0.,0.161829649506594,
0.33728011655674,0.430707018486,0.637101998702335,0.783997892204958,0.789371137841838,1.),(0.,
0.291685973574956,0.310378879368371,0.65187108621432,0.695528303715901,1.),.UNSPECIFIED.);
#460=CARTESIAN_POINT('',(100.,-375.,100.));
#461=CARTESIAN_POINT('',(100.,-373.64886297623,99.9677090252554));
#462=CARTESIAN_POINT('',(100.,-372.297276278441,99.9532853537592));
#463=CARTESIAN_POINT('',(100.,-369.594041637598,99.9609303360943));
#464=CARTESIAN_POINT('',(100.,-368.242393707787,99.9830035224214));
#465=CARTESIAN_POINT('',(100.,-365.540176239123,100.064409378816));
#466=CARTESIAN_POINT('',(100.,-364.18960672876,100.123743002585));
#467=CARTESIAN_POINT('',(100.,-361.490695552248,100.280274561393));
#468=CARTESIAN_POINT('',(100.,-360.14235382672,100.377471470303));
#469=CARTESIAN_POINT('',(100.,-357.449035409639,100.610198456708));
#470=CARTESIAN_POINT('',(100.,-356.104058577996,100.745726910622));
#471=CARTESIAN_POINT('',(100.,-353.418598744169,101.055431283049));
#472=CARTESIAN_POINT('',(100.,-352.078115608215,101.229606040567));
#473=CARTESIAN_POINT('',(100.,-349.422155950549,101.613949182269));
#474=CARTESIAN_POINT('',(100.,-348.106598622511,101.823559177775));
#475=CARTESIAN_POINT('',(100.,-345.48211629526,102.280425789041));
#476=CARTESIAN_POINT('',(100.,-344.173190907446,102.527680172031));
#477=CARTESIAN_POINT('',(100.,-341.563030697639,103.059639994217));
#478=CARTESIAN_POINT('',(100.,-340.261795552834,103.344343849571));
#479=CARTESIAN_POINT('',(100.,-337.66803538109,103.950836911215));
#480=CARTESIAN_POINT('',(100.,-336.375510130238,104.272625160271));
#481=CARTESIAN_POINT('',(100.,-333.800142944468,104.952753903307));
#482=CARTESIAN_POINT('',(100.,-332.517300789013,105.311093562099));
#483=CARTESIAN_POINT('',(100.,-329.962257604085,106.063607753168));
#484=CARTESIAN_POINT('',(99.9999999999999,-328.69005608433,106.457780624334));
#485=CARTESIAN_POINT('',(99.9999999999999,-325.566653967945,107.473053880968));
#486=CARTESIAN_POINT('',(100.,-323.72196403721,108.114292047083));
#487=CARTESIAN_POINT('',(100.,-320.058941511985,109.468978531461));
#488=CARTESIAN_POINT('',(100.,-318.240614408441,110.182441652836));
#489=CARTESIAN_POINT('',(100.,-314.631845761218,111.677942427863));
#490=CARTESIAN_POINT('',(100.,-312.84141177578,112.459998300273));
#491=CARTESIAN_POINT('',(100.,-309.289784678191,114.088499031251));
#492=CARTESIAN_POINT('',(100.,-307.528596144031,114.934953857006));
#493=CARTESIAN_POINT('',(100.,-304.036581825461,116.687578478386));
#494=CARTESIAN_POINT('',(100.,-302.305751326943,117.593738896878));
#495=CARTESIAN_POINT('',(100.,-298.867045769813,119.465195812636));
#496=CARTESIAN_POINT('',(100.,-297.159296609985,120.430723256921));
#497=CARTESIAN_POINT('',(100.,-293.774101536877,122.412530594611));
#498=CARTESIAN_POINT('',(100.,-292.096648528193,123.428798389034));
#499=CARTESIAN_POINT('',(100.,-288.770785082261,125.507567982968));
#500=CARTESIAN_POINT('',(100.,-287.122373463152,126.570067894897));
#501=CARTESIAN_POINT('',(100.,-283.853275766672,128.736707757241));
#502=CARTESIAN_POINT('',(99.9999999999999,-282.232588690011,129.840846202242));
#503=CARTESIAN_POINT('',(100.,-279.017597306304,132.086095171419));
#504=CARTESIAN_POINT('',(100.,-277.423287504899,133.227197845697));
#505=CARTESIAN_POINT('',(100.,-273.297831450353,136.245332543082));
#506=CARTESIAN_POINT('',(100.,-270.785748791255,138.148439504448));
#507=CARTESIAN_POINT('',(99.9999999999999,-265.814985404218,142.02266355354));
#508=CARTESIAN_POINT('',(100.,-263.356303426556,143.993779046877));
#509=CARTESIAN_POINT('',(100.,-258.481070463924,147.989212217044));
#510=CARTESIAN_POINT('',(100.,-256.064536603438,150.013550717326));
#511=CARTESIAN_POINT('',(100.,-251.262638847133,154.100825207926));
#512=CARTESIAN_POINT('',(100.,-248.877289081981,156.163777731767));
#513=CARTESIAN_POINT('',(100.,-244.126859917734,160.313788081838));
#514=CARTESIAN_POINT('',(100.,-241.761784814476,162.400850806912));
#515=CARTESIAN_POINT('',(100.,-237.034282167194,166.590434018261));
#516=CARTESIAN_POINT('',(99.9999999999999,-234.671877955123,168.692980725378));
#517=CARTESIAN_POINT('',(99.9999999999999,-229.944356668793,172.893501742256));
#518=CARTESIAN_POINT('',(99.9999999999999,-227.57924071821,174.991477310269));
#519=CARTESIAN_POINT('',(99.9999999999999,-222.833846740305,179.168217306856));
#520=CARTESIAN_POINT('',(99.9999999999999,-220.453575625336,181.246989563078));
#521=CARTESIAN_POINT('',(99.9999999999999,-215.664765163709,185.370035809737));
#522=CARTESIAN_POINT('',(99.9999999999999,-213.256237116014,187.414322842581));
#523=CARTESIAN_POINT('',(99.9999999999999,-209.611775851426,190.442563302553));
#524=CARTESIAN_POINT('',(100.,-208.391699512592,191.445594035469));
#525=CARTESIAN_POINT('',(99.9999999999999,-205.939315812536,193.436576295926));
#526=CARTESIAN_POINT('',(99.9999999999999,-204.707008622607,194.424528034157));
#527=CARTESIAN_POINT('',(99.9999999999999,-202.192992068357,196.410927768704));
#528=CARTESIAN_POINT('',(99.9999999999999,-200.910878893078,197.408865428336));
#529=CARTESIAN_POINT('',(100.,-198.32994976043,199.383408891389));
#530=CARTESIAN_POINT('',(99.9999999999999,-197.031130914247,200.360010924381));
#531=CARTESIAN_POINT('',(99.9999999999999,-194.415115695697,202.28866785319));
#532=CARTESIAN_POINT('',(99.9999999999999,-193.09791705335,203.240719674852));
#533=CARTESIAN_POINT('',(99.9999999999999,-190.443371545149,205.116928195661));
#534=CARTESIAN_POINT('',(99.9999999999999,-189.106020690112,206.041079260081));
#535=CARTESIAN_POINT('',(99.9999999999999,-186.409292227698,207.857991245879));
#536=CARTESIAN_POINT('',(99.9999999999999,-185.049905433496,208.750738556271));
#537=CARTESIAN_POINT('',(99.9999999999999,-182.317269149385,210.494692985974));
#538=CARTESIAN_POINT('',(99.9999999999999,-180.944169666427,211.346134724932));
#539=CARTESIAN_POINT('',(99.9999999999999,-178.174059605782,213.009601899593));
#540=CARTESIAN_POINT('',(99.9999999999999,-176.777046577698,213.82162326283));
#541=CARTESIAN_POINT('',(99.9999999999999,-173.958700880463,215.401462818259));
#542=CARTESIAN_POINT('',(99.9999999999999,-172.537375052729,216.169293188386));
#543=CARTESIAN_POINT('',(99.9999999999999,-169.67002356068,217.655991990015));
#544=CARTESIAN_POINT('',(99.9999999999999,-168.224008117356,218.374880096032));
#545=CARTESIAN_POINT('',(99.9999999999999,-165.306777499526,219.758871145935));
#546=CARTESIAN_POINT('',(99.9999999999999,-163.835568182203,220.423986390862));
#547=CARTESIAN_POINT('',(99.9999999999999,-161.126109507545,221.581985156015));
#548=CARTESIAN_POINT('',(99.9999999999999,-159.892057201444,222.08465952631));
#549=CARTESIAN_POINT('',(99.9999999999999,-158.027587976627,222.804014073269));
#550=CARTESIAN_POINT('',(99.9999999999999,-157.403828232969,223.038035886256));
#551=CARTESIAN_POINT('',(99.9999999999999,-156.151901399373,223.493998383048));
#552=CARTESIAN_POINT('',(99.9999999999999,-155.523734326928,223.71593911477));
#553=CARTESIAN_POINT('',(99.9999999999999,-154.263108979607,224.147139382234));
#554=CARTESIAN_POINT('',(99.9999999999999,-153.630651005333,224.356399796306));
#555=CARTESIAN_POINT('',(99.9999999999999,-152.361698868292,224.762276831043));
#556=CARTESIAN_POINT('',(99.9999999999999,-151.725204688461,224.958893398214));
#557=CARTESIAN_POINT('',(99.9999999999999,-149.810216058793,225.529988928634));
#558=CARTESIAN_POINT('',(99.9999999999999,-148.526090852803,225.885756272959));
#559=CARTESIAN_POINT('',(99.9999999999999,-145.945589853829,226.54853329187));
#560=CARTESIAN_POINT('',(99.9999999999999,-144.649215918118,226.855550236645));
#561=CARTESIAN_POINT('',(99.9999999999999,-142.042398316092,227.423213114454));
#562=CARTESIAN_POINT('',(99.9999999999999,-140.731924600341,227.683720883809));
#563=CARTESIAN_POINT('',(99.9999999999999,-138.10250527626,228.158924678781));
#564=CARTESIAN_POINT('',(99.9999999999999,-136.783558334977,228.373613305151));
#565=CARTESIAN_POINT('',(99.9999999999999,-134.13892535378,228.758905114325));
#566=CARTESIAN_POINT('',(99.9999999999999,-132.813237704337,228.929497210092));
#567=CARTESIAN_POINT('',(99.9999999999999,-130.156855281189,229.228338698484));
#568=CARTESIAN_POINT('',(99.9999999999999,-128.826159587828,229.356579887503));
#569=CARTESIAN_POINT('',(99.9999999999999,-126.161520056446,229.572475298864));
#570=CARTESIAN_POINT('',(99.9999999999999,-124.827576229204,229.660129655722));
#571=CARTESIAN_POINT('',(99.9999999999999,-121.564844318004,229.826959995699));
#572=CARTESIAN_POINT('',(99.9999999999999,-119.634956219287,229.885085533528));
#573=CARTESIAN_POINT('',(99.9999999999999,-115.774573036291,229.925694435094));
#574=CARTESIAN_POINT('',(99.9999999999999,-113.844077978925,229.908180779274));
#575=CARTESIAN_POINT('',(99.9999999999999,-109.984652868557,229.802520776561));
#576=CARTESIAN_POINT('',(99.9999999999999,-108.055723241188,229.714359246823));
#577=CARTESIAN_POINT('',(99.9999999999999,-104.201688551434,229.472070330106));
#578=CARTESIAN_POINT('',(99.9999999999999,-102.276584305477,229.317930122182));
#579=CARTESIAN_POINT('',(99.9999999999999,-98.4324550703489,228.948079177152));
#580=CARTESIAN_POINT('',(99.9999999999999,-96.5134297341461,228.732372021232));
#581=CARTESIAN_POINT('',(99.9999999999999,-92.6813451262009,228.243263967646));
#582=CARTESIAN_POINT('',(99.9999999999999,-90.7682912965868,227.969820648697));
#583=CARTESIAN_POINT('',(99.9999999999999,-86.9511553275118,227.369170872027));
#584=CARTESIAN_POINT('',(99.9999999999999,-85.0470711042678,227.041977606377));
#585=CARTESIAN_POINT('',(99.9999999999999,-81.2484726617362,226.337297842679));
#586=CARTESIAN_POINT('',(99.9999999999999,-79.3539574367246,225.959816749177));
#587=CARTESIAN_POINT('',(99.9999999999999,-75.5751362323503,225.157807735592));
#588=CARTESIAN_POINT('',(99.9999999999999,-73.6908292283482,224.733284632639));
#589=CARTESIAN_POINT('',(99.9999999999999,-69.9331129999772,223.840282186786));
#590=CARTESIAN_POINT('',(99.9999999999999,-68.0597015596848,223.371812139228));
#591=CARTESIAN_POINT('',(99.9999999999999,-63.6713211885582,222.222903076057));
#592=CARTESIAN_POINT('',(99.9999999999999,-61.1607670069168,221.525570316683));
#593=CARTESIAN_POINT('',(99.9999999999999,-56.1595542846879,220.062560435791));
#594=CARTESIAN_POINT('',(99.9999999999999,-53.6688971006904,219.2968786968));
#595=CARTESIAN_POINT('',(99.9999999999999,-48.7061208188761,217.703115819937));
#596=CARTESIAN_POINT('',(99.9999999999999,-46.2340129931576,216.874999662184));
#597=CARTESIAN_POINT('',(99.9999999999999,-41.3091851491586,215.16296159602));
#598=CARTESIAN_POINT('',(99.9999999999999,-38.8564655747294,214.279038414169));
#599=CARTESIAN_POINT('',(99.9999999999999,-33.9669968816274,212.460654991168));
#600=CARTESIAN_POINT('',(99.9999999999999,-31.5302668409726,211.526143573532));
#601=CARTESIAN_POINT('',(99.9999999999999,-26.6739508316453,209.613656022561));
#602=CARTESIAN_POINT('',(99.9999999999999,-24.2543649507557,208.63567966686));
#603=CARTESIAN_POINT('',(99.9999999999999,-19.429823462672,206.64227672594));
#604=CARTESIAN_POINT('',(99.9999999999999,-17.0248726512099,205.626838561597));
#605=CARTESIAN_POINT('',(99.9999999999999,-12.2282167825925,203.565226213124));
#606=CARTESIAN_POINT('',(99.9999999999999,-9.83651170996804,202.519052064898));
#607=CARTESIAN_POINT('',(99.9999999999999,-5.03972660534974,200.39178791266));
#608=CARTESIAN_POINT('',(99.9999999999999,-2.63475599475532,199.310451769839));
#609=CARTESIAN_POINT('',(99.9999999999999,2.16704791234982,197.129898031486));
#610=CARTESIAN_POINT('',(99.9999999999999,4.56388119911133,196.030680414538));
#611=CARTESIAN_POINT('',(99.9999999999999,9.35044162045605,193.822214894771));
#612=CARTESIAN_POINT('',(99.9999999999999,11.7401730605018,192.712976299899));
#613=CARTESIAN_POINT('',(99.9999999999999,16.5177902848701,190.490528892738));
#614=CARTESIAN_POINT('',(99.9999999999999,18.9056760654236,189.377320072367));
#615=CARTESIAN_POINT('',(99.9999999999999,23.6812735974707,187.15477202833));
#616=CARTESIAN_POINT('',(99.9999999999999,26.0689843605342,186.045430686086));
#617=CARTESIAN_POINT('',(99.9999999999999,30.8491606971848,183.837057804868));
#618=CARTESIAN_POINT('',(99.9999999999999,33.2416262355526,182.738026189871));
#619=CARTESIAN_POINT('',(99.9999999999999,38.033638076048,180.558078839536));
#620=CARTESIAN_POINT('',(99.9999999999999,40.433181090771,179.4771558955));
#621=CARTESIAN_POINT('',(99.9999999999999,45.2434777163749,177.340580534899));
#622=CARTESIAN_POINT('',(100.,47.6542311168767,176.284927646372));
#623=CARTESIAN_POINT('',(99.9999999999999,51.8418364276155,174.485358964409));
#624=CARTESIAN_POINT('',(99.9999999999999,53.615374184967,173.733738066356));
#625=CARTESIAN_POINT('',(99.9999999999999,57.1715636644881,172.251386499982));
#626=CARTESIAN_POINT('',(99.9999999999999,58.9542170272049,171.520659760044));
#627=CARTESIAN_POINT('',(99.9999999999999,62.5299294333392,170.083403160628));
#628=CARTESIAN_POINT('',(99.9999999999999,64.3229916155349,169.376881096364));
#629=CARTESIAN_POINT('',(99.9999999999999,67.9208659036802,167.99146917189));
#630=CARTESIAN_POINT('',(99.9999999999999,69.7256837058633,167.312594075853));
#631=CARTESIAN_POINT('',(99.9999999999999,73.3484739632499,165.986071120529));
#632=CARTESIAN_POINT('',(99.9999999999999,75.1664560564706,165.33844952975));
#633=CARTESIAN_POINT('',(99.9999999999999,78.8170513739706,164.078202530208));
#634=CARTESIAN_POINT('',(99.9999999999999,80.6496798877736,163.46562130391));
#635=CARTESIAN_POINT('',(99.9999999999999,84.2930576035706,162.291761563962));
#636=CARTESIAN_POINT('',(99.9999999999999,86.1035641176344,161.729731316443));
#637=CARTESIAN_POINT('',(99.9999999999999,89.7384482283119,160.650133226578));
#638=CARTESIAN_POINT('',(99.9999999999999,91.562829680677,160.132578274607));
#639=CARTESIAN_POINT('',(99.9999999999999,94.3091261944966,159.39533539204));
#640=CARTESIAN_POINT('',(99.9999999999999,95.2258390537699,159.156183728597));
#641=CARTESIAN_POINT('',(99.9999999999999,97.0628102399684,158.691869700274));
#642=CARTESIAN_POINT('',(99.9999999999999,97.983068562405,158.46670731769));
#643=CARTESIAN_POINT('',(99.9999999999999,99.8257959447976,158.031826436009));
#644=CARTESIAN_POINT('',(99.9999999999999,100.748259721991,157.822085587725));
#645=CARTESIAN_POINT('',(99.9999999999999,102.596745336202,157.418939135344));
#646=CARTESIAN_POINT('',(99.9999999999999,103.52276713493,157.225533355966));
#647=CARTESIAN_POINT('',(99.9999999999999,105.376760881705,156.856762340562));
#648=CARTESIAN_POINT('',(99.9999999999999,106.304726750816,156.681366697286));
#649=CARTESIAN_POINT('',(99.9999999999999,107.69923233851,156.432695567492));
#650=CARTESIAN_POINT('',(99.9999999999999,108.164494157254,156.352208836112));
#651=CARTESIAN_POINT('',(99.9999999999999,109.095860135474,156.196248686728));
#652=CARTESIAN_POINT('',(99.9999999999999,109.561964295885,156.120775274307));
#653=CARTESIAN_POINT('',(99.9999999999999,110.494374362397,155.975186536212));
#654=CARTESIAN_POINT('',(99.9999999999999,110.960679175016,155.9050642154));
#655=CARTESIAN_POINT('',(99.9999999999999,111.894061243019,155.770179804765));
#656=CARTESIAN_POINT('',(99.9999999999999,112.361138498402,155.705417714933));
#657=CARTESIAN_POINT('',(99.9999999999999,113.763437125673,155.519130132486));
#658=CARTESIAN_POINT('',(99.9999999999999,114.699733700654,155.405602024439));
#659=CARTESIAN_POINT('',(99.9999999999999,116.5811833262,155.198973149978));
#660=CARTESIAN_POINT('',(99.9999999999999,117.526352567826,155.10602055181));
#661=CARTESIAN_POINT('',(99.9999999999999,119.418521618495,154.941142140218));
#662=CARTESIAN_POINT('',(99.9999999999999,120.365521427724,154.869216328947));
#663=CARTESIAN_POINT('',(99.9999999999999,122.261700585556,154.745726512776));
#664=CARTESIAN_POINT('',(99.9999999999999,123.210881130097,154.69418095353));
#665=CARTESIAN_POINT('',(99.9999999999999,125.110098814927,154.610728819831));
#666=CARTESIAN_POINT('',(99.9999999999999,126.060135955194,154.578822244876));
#667=CARTESIAN_POINT('',(99.9999999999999,127.962043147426,154.53360556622));
#668=CARTESIAN_POINT('',(99.9999999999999,128.913913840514,154.520322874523));
#669=CARTESIAN_POINT('',(99.9999999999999,130.817752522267,154.511245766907));
#670=CARTESIAN_POINT('',(99.9999999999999,131.769720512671,154.515451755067));
#671=CARTESIAN_POINT('',(99.9999999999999,133.674924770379,154.540014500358));
#672=CARTESIAN_POINT('',(99.9999999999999,134.628160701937,154.560396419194));
#673=CARTESIAN_POINT('',(99.9999999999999,136.53421259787,154.615832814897));
#674=CARTESIAN_POINT('',(99.9999999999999,137.487028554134,154.650887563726));
#675=CARTESIAN_POINT('',(99.9999999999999,140.346643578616,154.775743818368));
#676=CARTESIAN_POINT('',(99.9999999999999,142.252589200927,154.885204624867));
#677=CARTESIAN_POINT('',(99.9999999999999,146.061789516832,155.142576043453));
#678=CARTESIAN_POINT('',(99.9999999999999,147.965044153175,155.290487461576));
#679=CARTESIAN_POINT('',(99.9999999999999,151.794038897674,155.612320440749));
#680=CARTESIAN_POINT('',(99.9999999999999,153.719752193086,155.786553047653));
#681=CARTESIAN_POINT('',(99.9999999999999,157.56791927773,156.144614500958));
#682=CARTESIAN_POINT('',(99.9999999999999,159.490374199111,156.328431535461));
#683=CARTESIAN_POINT('',(99.9999999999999,163.333732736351,156.691921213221));
#684=CARTESIAN_POINT('',(99.9999999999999,165.254635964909,156.871597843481));
#685=CARTESIAN_POINT('',(99.9999999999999,169.096453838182,157.214591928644));
#686=CARTESIAN_POINT('',(99.9999999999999,171.017367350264,157.377921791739));
#687=CARTESIAN_POINT('',(99.9999999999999,174.860604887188,157.677814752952));
#688=CARTESIAN_POINT('',(99.9999999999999,176.782928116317,157.814387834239));
#689=CARTESIAN_POINT('',(99.9999999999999,180.63021386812,158.052273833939));
#690=CARTESIAN_POINT('',(99.9999999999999,182.555176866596,158.153579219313));
#691=CARTESIAN_POINT('',(99.9999999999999,186.400407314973,158.313959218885));
#692=CARTESIAN_POINT('',(99.9999999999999,188.32066874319,158.373174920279));
#693=CARTESIAN_POINT('',(99.9999999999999,192.163691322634,158.445212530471));
#694=CARTESIAN_POINT('',(99.9999999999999,194.086453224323,158.457995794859));
#695=CARTESIAN_POINT('',(99.9999999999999,197.932593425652,158.43398980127));
#696=CARTESIAN_POINT('',(99.9999999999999,199.85597158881,158.397177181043));
#697=CARTESIAN_POINT('',(99.9999999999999,203.70151337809,158.272333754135));
#698=CARTESIAN_POINT('',(99.9999999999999,205.623676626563,158.184291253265));
#699=CARTESIAN_POINT('',(99.9999999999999,209.465003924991,157.9566151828));
#700=CARTESIAN_POINT('',(99.9999999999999,211.384167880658,157.816980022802));
#701=CARTESIAN_POINT('',(99.9999999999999,215.217750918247,157.486763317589));
#702=CARTESIAN_POINT('',(99.9999999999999,217.132170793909,157.296190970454));
#703=CARTESIAN_POINT('',(99.9999999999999,220.950110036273,156.866031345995));
#704=CARTESIAN_POINT('',(99.9999999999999,222.853644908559,156.626581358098));
#705=CARTESIAN_POINT('',(99.9999999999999,226.653865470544,156.100225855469));
#706=CARTESIAN_POINT('',(99.9999999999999,228.550552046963,155.813326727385));
#707=CARTESIAN_POINT('',(99.9999999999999,232.336487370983,155.194230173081));
#708=CARTESIAN_POINT('',(99.9999999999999,234.225736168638,154.862033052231));
#709=CARTESIAN_POINT('',(99.9999999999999,237.996246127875,154.154690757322));
#710=CARTESIAN_POINT('',(99.9999999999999,239.877506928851,153.779543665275));
#711=CARTESIAN_POINT('',(99.9999999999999,243.63151353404,152.988754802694));
#712=CARTESIAN_POINT('',(99.9999999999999,245.504259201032,152.573112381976));
#713=CARTESIAN_POINT('',(99.9999999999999,249.24071113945,151.703825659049));
#714=CARTESIAN_POINT('',(99.9999999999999,251.104418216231,151.250184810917));
#715=CARTESIAN_POINT('',(99.9999999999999,255.084658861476,150.240849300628));
#716=CARTESIAN_POINT('',(99.9999999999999,257.199829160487,149.679780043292));
#717=CARTESIAN_POINT('',(99.9999999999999,261.417994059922,148.514723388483));
#718=CARTESIAN_POINT('',(99.9999999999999,263.520990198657,147.91074154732));
#719=CARTESIAN_POINT('',(99.9999999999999,267.71508267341,146.662995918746));
#720=CARTESIAN_POINT('',(99.9999999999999,269.806179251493,146.019232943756));
#721=CARTESIAN_POINT('',(99.9999999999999,273.976680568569,144.694871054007));
#722=CARTESIAN_POINT('',(99.9999999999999,276.056085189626,144.014271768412));
#723=CARTESIAN_POINT('',(99.9999999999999,280.203354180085,142.61899238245));
#724=CARTESIAN_POINT('',(99.9999999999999,282.271218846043,141.90431316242));
#725=CARTESIAN_POINT('',(99.9999999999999,286.400200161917,140.441782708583));
#726=CARTESIAN_POINT('',(99.9999999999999,288.46129258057,139.693863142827));
#727=CARTESIAN_POINT('',(99.9999999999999,292.57245753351,138.16862732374));
#728=CARTESIAN_POINT('',(99.9999999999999,294.622530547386,137.391312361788));
#729=CARTESIAN_POINT('',(99.9999999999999,298.712092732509,135.80934960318));
#730=CARTESIAN_POINT('',(99.9999999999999,300.751581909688,135.004701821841));
#731=CARTESIAN_POINT('',(99.9999999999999,304.820346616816,133.369972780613));
#732=CARTESIAN_POINT('',(99.9999999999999,306.849622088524,132.539891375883));
#733=CARTESIAN_POINT('',(99.9999999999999,310.89827296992,130.856045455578));
#734=CARTESIAN_POINT('',(99.9999999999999,312.917648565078,130.0022813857));
#735=CARTESIAN_POINT('',(99.9999999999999,316.641726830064,128.403627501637));
#736=CARTESIAN_POINT('',(99.9999999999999,318.347760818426,127.661835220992));
#737=CARTESIAN_POINT('',(99.9999999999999,321.753156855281,126.163216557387));
#738=CARTESIAN_POINT('',(99.9999999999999,323.452519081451,125.40639057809));
#739=CARTESIAN_POINT('',(99.9999999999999,326.844826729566,123.878497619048));
#740=CARTESIAN_POINT('',(99.9999999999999,328.537772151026,123.107430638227));
#741=CARTESIAN_POINT('',(99.9999999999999,331.91747759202,121.55179232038));
#742=CARTESIAN_POINT('',(99.9999999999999,333.604237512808,120.767220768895));
#743=CARTESIAN_POINT('',(99.9999999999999,336.971779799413,119.185260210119));
#744=CARTESIAN_POINT('',(99.9999999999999,338.652562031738,118.387870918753));
#745=CARTESIAN_POINT('',(99.9999999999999,342.008335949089,116.780916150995));
#746=CARTESIAN_POINT('',(99.9999999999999,343.683327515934,115.971350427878));
#747=CARTESIAN_POINT('',(99.9999999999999,347.018318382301,114.345211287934));
#748=CARTESIAN_POINT('',(99.9999999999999,348.678349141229,113.528702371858));
#749=CARTESIAN_POINT('',(99.9999999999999,351.992999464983,111.884790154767));
#750=CARTESIAN_POINT('',(99.9999999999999,353.647619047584,111.057386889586));
#751=CARTESIAN_POINT('',(99.9999999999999,356.951574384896,109.392208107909));
#752=CARTESIAN_POINT('',(99.9999999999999,358.60091027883,108.554432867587));
#753=CARTESIAN_POINT('',(99.9999999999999,361.894410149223,106.869001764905));
#754=CARTESIAN_POINT('',(99.9999999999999,363.538574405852,106.021346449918));
#755=CARTESIAN_POINT('',(99.9999999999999,366.821829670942,104.316622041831));
#756=CARTESIAN_POINT('',(99.9999999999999,368.460921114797,103.459553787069));
#757=CARTESIAN_POINT('',(99.9999999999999,371.734114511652,101.736437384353));
#758=CARTESIAN_POINT('',(99.9999999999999,373.368217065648,100.870390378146));
#759=CARTESIAN_POINT('',(99.9999999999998,375.,100.));
#760=B_SPLINE_CURVE_WITH_KNOTS('',3,(#460,#461,#462,#463,#464,#465,#466,#467,#468,#469,#470,
#471,#472,#473,#474,#475,#476,#477,#478,#479,#480,#481,#482,#483,#484,#485,#486,#487,#488,#489,
#490,#491,#492,#493,#494,#495,#496,#497,#498,#499,#500,#501,#502,#503,#504,#505,#506,#507,#508,
#509,#510,#511,#512,#513,#514,#515,#516,#517,#518,#519,#520,#521,#522,#523,#524,#525,#526,#527,
#528,#529,#530,#531,#532,#533,#534,#535,#536,#537,#538,#539,#540,#541,#542,#543,#544,#545,#546,
#547,#548,#549,#550,#551,#552,#553,#554,#555,#556,#557,#558,#559,#560,#561,#562,#563,#564,#565,
#566,#567,#568,#569,#570,#571,#572,#573,#574,#575,#576,#577,#578,#579,#580,#581,#582,#583,#584,
#585,#586,#587,#588,#589,#590,#591,#592,#593,#594,#595,#596,#597,#598,#599,#600,#601,#602,#603,
#604,#605,#606,#607,#608,#609,#610,#611,#612,#613,#614,#615,#616,#617,#618,#619,#620,#621,#622,
#623,#624,#625,#626,#627,#628,#629,#630,#631,#632,#633,#634,#635,#636,#637,#638,#639,#640,#641,
#642,#643,#644,#645,#646,#647,#648,#649,#650,#651,#652,#653,#654,#655,#656,#657,#658,#659,#660,
#661,#662,#663,#664,#665,#666,#667,#668,#669,#670,#671,#672,#673,#674,#675,#676,#677,#678,#679,
#680,#681,#682,#683,#684,#685,#686,#687,#688,#689,#690,#691,#692,#693,#694,#695,#696,#697,#698,
#699,#700,#701,#702,#703,#704,#705,#706,#707,#708,#709,#710,#711,#712,#713,#714,#715,#716,#717,
#718,#719,#720,#721,#722,#723,#724,#725,#726,#727,#728,#729,#730,#731,#732,#733,#734,#735,#736,
#737,#738,#739,#740,#741,#742,#743,#744,#745,#746,#747,#748,#749,#750,#751,#752,#753,#754,#755,
#756,#757,#758,#759),.UNSPECIFIED.,.F.,.F.,(4,2,2,2,2,2,2,2,2,2,2,2,2,2,2,2,2,2,2,2,2,2,2,2,2,2,
2,2,2,2,2,2,2,2,2,2,2,2,2,2,2,2,2,2,2,2,2,2,2,2,2,2,2,2,2,2,2,2,2,2,2,2,2,2,2,2,2,2,2,2,2,2,2,2,
2,2,2,2,2,2,2,2,2,2,2,2,2,2,2,2,2,2,2,2,2,2,2,2,2,2,2,2,2,2,2,2,2,2,2,2,2,2,2,2,2,2,2,2,2,2,2,2,
2,2,2,2,2,2,2,2,2,2,2,2,2,2,2,2,2,2,2,2,2,2,2,2,2,2,2,4),(0.,4.05448399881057,8.10947155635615,
12.164562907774,16.2195443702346,20.2743541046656,24.3290420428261,28.3249507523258,
32.3206225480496,36.3161254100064,40.311525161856,44.3068336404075,48.3019570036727,
54.1591899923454,60.017625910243,65.8776226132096,71.7385281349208,77.5985153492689,
83.4829508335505,89.3659898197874,95.2487888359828,101.131375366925,107.012720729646,
116.465817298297,125.918692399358,135.375322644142,144.836099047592,154.298832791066,
163.786459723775,173.271020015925,182.751526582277,192.228363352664,196.96661089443,
201.704792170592,206.578734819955,211.45353193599,216.328936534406,221.205319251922,
226.083790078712,230.93017073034,235.77705099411,240.622589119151,245.466167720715,
250.308635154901,254.305231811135,256.303772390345,258.302305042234,260.300699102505,
262.299101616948,266.295511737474,270.291325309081,274.298818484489,278.306958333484,
282.31610495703,286.326027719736,290.335937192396,296.126535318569,301.916905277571,
307.708519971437,313.501260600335,319.293664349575,325.090338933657,330.885592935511,
336.680224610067,342.474263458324,348.267079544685,356.082761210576,363.89897128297,
371.719598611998,379.540404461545,387.369275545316,395.198186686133,403.029538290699,
410.860880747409,418.771438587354,426.682005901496,434.585857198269,442.489724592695,
450.388210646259,458.286638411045,466.181843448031,474.076900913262,479.855485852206,
485.635150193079,491.416658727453,497.201215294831,502.990551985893,508.787034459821,
514.473771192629,520.162150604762,523.004243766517,525.846333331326,528.684219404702,
531.522075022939,534.35505774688,535.771552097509,537.188048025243,538.602659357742,
540.017270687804,542.846468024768,545.695420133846,548.544372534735,551.395897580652,
554.247422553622,557.103140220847,559.958923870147,562.819158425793,565.679445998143,
571.406081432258,577.132836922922,582.933500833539,588.727177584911,594.515020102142,
600.298435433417,606.079688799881,611.862176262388,617.625187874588,623.392994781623,
629.163519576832,634.935362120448,640.707382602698,646.478361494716,652.233348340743,
657.98756119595,663.741735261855,669.496166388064,675.250689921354,681.004690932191,
687.569149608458,694.13275986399,700.696236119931,707.259778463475,713.823151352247,
720.40070435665,726.977968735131,733.555229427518,740.13252758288,746.709702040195,
752.290602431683,757.87135317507,763.452104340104,769.032944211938,774.613907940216,
780.194984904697,785.744853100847,791.294703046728,796.844405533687,802.393802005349,
807.942708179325,813.490917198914),.UNSPECIFIED.);
#761=CARTESIAN_POINT('',(100.,-375.,100.));
#762=VERTEX_POINT('',#761);
#763=CARTESIAN_POINT('',(99.9999999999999,375.,100.));
#764=VERTEX_POINT('',#763);
#765=EDGE_CURVE('E11',#762,#764,#760,.T.);
#766=CARTESIAN_POINT('',(-750.,-375.,100.));
#767=CARTESIAN_POINT('',(-644.685568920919,-375.,100.));
#768=CARTESIAN_POINT('',(-536.684515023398,-375.,100.));
#769=CARTESIAN_POINT('',(-355.235514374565,-375.,100.));
#770=CARTESIAN_POINT('',(-175.903454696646,-375.,100.));
#771=CARTESIAN_POINT('',(47.4554331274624,-375.,100.));
#772=CARTESIAN_POINT('',(285.091607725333,-375.,100.));
#773=CARTESIAN_POINT('',(500.445116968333,-375.,100.));
#774=CARTESIAN_POINT('',(669.085175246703,-375.,100.));
#775=CARTESIAN_POINT('',(750.,-375.,100.));
#776=B_SPLINE_CURVE_WITH_KNOTS('',3,(#766,#767,#768,#769,#770,#771,#772,#773,#774,#775),
.UNSPECIFIED.,.F.,.F.,(4,1,1,1,1,1,1,4),(0.,0.210628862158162,0.216002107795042,
0.362898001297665,0.569292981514,0.66271988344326,0.838170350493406,1.),.UNSPECIFIED.);
#777=EDGE_CURVE('E97',#762,#320,#776,.T.);
#778=CARTESIAN_POINT('',(750.,375.,100.));
#779=CARTESIAN_POINT('',(669.085175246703,375.,100.));
#780=CARTESIAN_POINT('',(500.445116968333,375.,100.));
#781=CARTESIAN_POINT('',(285.091607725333,375.,100.));
#782=CARTESIAN_POINT('',(47.4554331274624,375.,100.));
#783=CARTESIAN_POINT('',(-175.903454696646,375.,100.));
#784=CARTESIAN_POINT('',(-355.235514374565,375.,100.));
#785=CARTESIAN_POINT('',(-536.684515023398,375.,100.));
#786=CARTESIAN_POINT('',(-644.685568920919,375.,100.));
#787=CARTESIAN_POINT('',(-750.,375.,100.));
#788=B_SPLINE_CURVE_WITH_KNOTS('',3,(#778,#779,#780,#781,#782,#783,#784,#785,#786,#787),
.UNSPECIFIED.,.F.,.F.,(4,1,1,1,1,1,1,4),(0.,0.161829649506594,0.33728011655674,0.430707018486,
0.637101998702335,0.783997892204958,0.789371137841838,1.),.UNSPECIFIED.);
#789=EDGE_CURVE('E94',#318,#764,#788,.T.);
#790=ORIENTED_EDGE('',*,*,#765,.F.);
#791=ORIENTED_EDGE('',*,*,#777,.T.);
#792=ORIENTED_EDGE('',*,*,#321,.F.);
#793=ORIENTED_EDGE('',*,*,#789,.T.);
#794=EDGE_LOOP('',(#790,#791,#792,#793));
#795=FACE_BOUND('',#794,.T.);
#796=ADVANCED_FACE('F110',(#795),#459,.F.);
#797=CARTESIAN_POINT('',(-750.,375.,253.111113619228));
#798=DIRECTION('',(0.,-1.,0.));
#799=DIRECTION('',(0.,0.,-1.));
#800=AXIS2_PLACEMENT_3D('',#797,#798,#799);
#801=PLANE('',#800);
#802=DIRECTION('',(0.,0.,-1.));
#803=VECTOR('',#802,1.);
#804=CARTESIAN_POINT('',(99.9999999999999,375.,253.120113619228));
#805=LINE('',#804,#803);
#806=EDGE_CURVE('E154',#764,#366,#805,.T.);
#807=ORIENTED_EDGE('',*,*,#806,.F.);
#808=ORIENTED_EDGE('',*,*,#789,.F.);
#809=ORIENTED_EDGE('',*,*,#343,.T.);
#810=ORIENTED_EDGE('',*,*,#373,.T.);
#811=EDGE_LOOP('',(#807,#808,#809,#810));
#812=FACE_BOUND('',#811,.T.);
#813=ADVANCED_FACE('F121',(#812),#801,.F.);
#814=CARTESIAN_POINT('',(-750.,-375.,253.111113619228));
#815=DIRECTION('',(0.,1.,0.));
#816=DIRECTION('',(0.,0.,1.));
#817=AXIS2_PLACEMENT_3D('',#814,#815,#816);
#818=PLANE('',#817);
#819=DIRECTION('',(0.,0.,-1.));
#820=VECTOR('',#819,1.);
#821=CARTESIAN_POINT('',(100.,-375.,253.120113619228));
#822=LINE('',#821,#820);
#823=EDGE_CURVE('E56',#762,#358,#822,.T.);
#824=ORIENTED_EDGE('',*,*,#823,.T.);
#825=ORIENTED_EDGE('',*,*,#359,.T.);
#826=ORIENTED_EDGE('',*,*,#329,.F.);
#827=ORIENTED_EDGE('',*,*,#777,.F.);
#828=EDGE_LOOP('',(#824,#825,#826,#827));
#829=FACE_BOUND('',#828,.T.);
#830=ADVANCED_FACE('F37',(#829),#818,.F.);
#831=CARTESIAN_POINT('',(99.9999999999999,375.,253.120113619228));
#832=DIRECTION('',(-1.,0.,0.));
#833=DIRECTION('',(0.,-1.,0.));
#834=AXIS2_PLACEMENT_3D('',#831,#832,#833);
#835=PLANE('',#834);
#836=ORIENTED_EDGE('',*,*,#765,.T.);
#837=ORIENTED_EDGE('',*,*,#806,.T.);
#838=ORIENTED_EDGE('',*,*,#367,.F.);
#839=ORIENTED_EDGE('',*,*,#823,.F.);
#840=EDGE_LOOP('',(#836,#837,#838,#839));
#841=FACE_BOUND('',#840,.T.);
#842=ADVANCED_FACE('F145',(#841),#835,.T.);
#843=CLOSED_SHELL('',(#347,#378,#796,#813,#830,#842));
#844=MANIFOLD_SOLID_BREP('B2',#843);
#845=ADVANCED_BREP_SHAPE_REPRESENTATION('',(#18,#844),#14);
#846=SHAPE_DEFINITION_REPRESENTATION(#9,#845);
ENDSEC;
END-ISO-10303-21;
